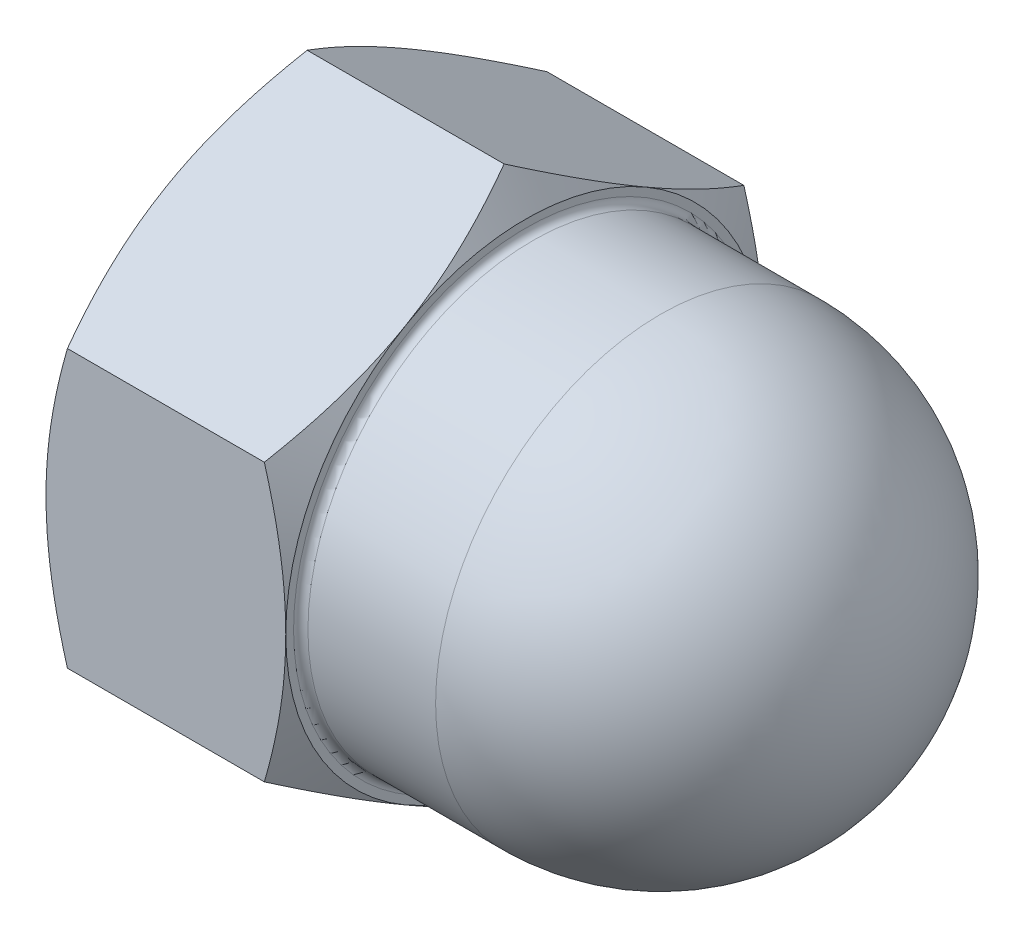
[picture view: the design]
ISO-10303-21;
HEADER;
FILE_DESCRIPTION(('STEP AP214'),'2;1');
FILE_NAME('part.step','',(''),(''),'','','');
FILE_SCHEMA(('AUTOMOTIVE_DESIGN { 1 0 10303 214 1 1 1 1 }'));
ENDSEC;
DATA;
#1=APPLICATION_CONTEXT('core data for automotive mechanical design processes');
#2=APPLICATION_PROTOCOL_DEFINITION('international standard','automotive_design',2000,#1);
#3=PRODUCT_CONTEXT('',#1,'mechanical');
#4=PRODUCT('Part','Part','',(#3));
#5=PRODUCT_RELATED_PRODUCT_CATEGORY('part','',(#4));
#6=PRODUCT_DEFINITION_FORMATION('','',#4);
#7=PRODUCT_DEFINITION_CONTEXT('part definition',#1,'design');
#8=PRODUCT_DEFINITION('design','',#6,#7);
#9=PRODUCT_DEFINITION_SHAPE('','',#8);
#10=(LENGTH_UNIT() NAMED_UNIT(*) SI_UNIT(.MILLI.,.METRE.));
#11=(NAMED_UNIT(*) PLANE_ANGLE_UNIT() SI_UNIT($,.RADIAN.));
#12=(NAMED_UNIT(*) SI_UNIT($,.STERADIAN.) SOLID_ANGLE_UNIT());
#13=UNCERTAINTY_MEASURE_WITH_UNIT(LENGTH_MEASURE(1.E-05),#10,'distance_accuracy_value','');
#14=(GEOMETRIC_REPRESENTATION_CONTEXT(3) GLOBAL_UNCERTAINTY_ASSIGNED_CONTEXT((#13)) GLOBAL_UNIT_ASSIGNED_CONTEXT((#10,
#11,#12)) REPRESENTATION_CONTEXT('',''));
#15=CARTESIAN_POINT('',(0.,0.,0.));
#16=DIRECTION('',(0.,0.,1.));
#17=DIRECTION('',(1.,0.,0.));
#18=AXIS2_PLACEMENT_3D('',#15,#16,#17);
#19=CARTESIAN_POINT('',(0.,4.61880215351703,0.));
#20=DIRECTION('',(-1.,0.,0.));
#21=DIRECTION('',(0.,0.,1.));
#22=AXIS2_PLACEMENT_3D('',#19,#20,#21);
#23=PLANE('',#22);
#24=CARTESIAN_POINT('',(0.,0.,0.));
#25=DIRECTION('',(-1.,0.,0.));
#26=DIRECTION('',(0.,0.,1.));
#27=AXIS2_PLACEMENT_3D('',#24,#25,#26);
#28=CIRCLE('',#27,2.5);
#29=CARTESIAN_POINT('',(0.,0.,2.5));
#30=VERTEX_POINT('',#29);
#31=EDGE_CURVE('E301',#30,#30,#28,.T.);
#32=ORIENTED_EDGE('',*,*,#31,.F.);
#33=EDGE_LOOP('',(#32));
#34=FACE_BOUND('',#33,.T.);
#35=CARTESIAN_POINT('',(0.,0.,0.));
#36=DIRECTION('',(-1.,0.,0.));
#37=DIRECTION('',(0.,0.,1.));
#38=AXIS2_PLACEMENT_3D('',#35,#36,#37);
#39=CIRCLE('',#38,4.);
#40=CARTESIAN_POINT('',(0.,-3.46410161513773,2.00000000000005));
#41=VERTEX_POINT('',#40);
#42=CARTESIAN_POINT('',(0.,0.,4.));
#43=VERTEX_POINT('',#42);
#44=EDGE_CURVE('E183',#41,#43,#39,.T.);
#45=ORIENTED_EDGE('',*,*,#44,.T.);
#46=CARTESIAN_POINT('',(0.,0.,0.));
#47=DIRECTION('',(-1.,0.,0.));
#48=DIRECTION('',(0.,0.,1.));
#49=AXIS2_PLACEMENT_3D('',#46,#47,#48);
#50=CIRCLE('',#49,4.);
#51=CARTESIAN_POINT('',(0.,3.46410161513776,1.99999999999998));
#52=VERTEX_POINT('',#51);
#53=EDGE_CURVE('E293',#43,#52,#50,.T.);
#54=ORIENTED_EDGE('',*,*,#53,.T.);
#55=CARTESIAN_POINT('',(0.,3.46410161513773,-2.00000000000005));
#56=VERTEX_POINT('',#55);
#57=EDGE_CURVE('E182',#52,#56,#39,.T.);
#58=ORIENTED_EDGE('',*,*,#57,.T.);
#59=CARTESIAN_POINT('',(0.,0.,-4.));
#60=VERTEX_POINT('',#59);
#61=EDGE_CURVE('E349',#56,#60,#39,.T.);
#62=ORIENTED_EDGE('',*,*,#61,.T.);
#63=CARTESIAN_POINT('',(0.,-3.46410161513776,-1.99999999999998));
#64=VERTEX_POINT('',#63);
#65=EDGE_CURVE('E348',#60,#64,#39,.T.);
#66=ORIENTED_EDGE('',*,*,#65,.T.);
#67=EDGE_CURVE('E346',#64,#41,#39,.T.);
#68=ORIENTED_EDGE('',*,*,#67,.T.);
#69=EDGE_LOOP('',(#45,#54,#58,#62,#66,#68));
#70=FACE_BOUND('',#69,.T.);
#71=ADVANCED_FACE('F32',(#34,#70),#23,.T.);
#72=CARTESIAN_POINT('',(4.,4.61880215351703,0.));
#73=DIRECTION('',(-1.,0.,0.));
#74=DIRECTION('',(0.,0.,1.));
#75=AXIS2_PLACEMENT_3D('',#72,#73,#74);
#76=PLANE('',#75);
#77=CARTESIAN_POINT('',(4.,0.,0.));
#78=DIRECTION('',(-1.,0.,0.));
#79=DIRECTION('',(0.,0.,1.));
#80=AXIS2_PLACEMENT_3D('',#77,#78,#79);
#81=CIRCLE('',#80,3.87);
#82=CARTESIAN_POINT('',(4.,0.,3.87));
#83=VERTEX_POINT('',#82);
#84=EDGE_CURVE('E11',#83,#83,#81,.T.);
#85=ORIENTED_EDGE('',*,*,#84,.T.);
#86=EDGE_LOOP('',(#85));
#87=FACE_BOUND('',#86,.T.);
#88=CARTESIAN_POINT('',(4.,0.,0.));
#89=DIRECTION('',(-1.,0.,0.));
#90=DIRECTION('',(0.,0.,1.));
#91=AXIS2_PLACEMENT_3D('',#88,#89,#90);
#92=CIRCLE('',#91,4.);
#93=CARTESIAN_POINT('',(4.,0.,4.));
#94=VERTEX_POINT('',#93);
#95=CARTESIAN_POINT('',(4.,3.46410161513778,1.99999999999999));
#96=VERTEX_POINT('',#95);
#97=EDGE_CURVE('E294',#94,#96,#92,.T.);
#98=ORIENTED_EDGE('',*,*,#97,.F.);
#99=CARTESIAN_POINT('',(4.,-3.46410161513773,2.00000000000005));
#100=VERTEX_POINT('',#99);
#101=EDGE_CURVE('E47',#100,#94,#92,.T.);
#102=ORIENTED_EDGE('',*,*,#101,.F.);
#103=CARTESIAN_POINT('',(4.,-3.46410161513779,-2.));
#104=VERTEX_POINT('',#103);
#105=EDGE_CURVE('E283',#104,#100,#92,.T.);
#106=ORIENTED_EDGE('',*,*,#105,.F.);
#107=CARTESIAN_POINT('',(4.,0.,-4.));
#108=VERTEX_POINT('',#107);
#109=EDGE_CURVE('E55',#108,#104,#92,.T.);
#110=ORIENTED_EDGE('',*,*,#109,.F.);
#111=CARTESIAN_POINT('',(4.,3.46410161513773,-2.00000000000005));
#112=VERTEX_POINT('',#111);
#113=EDGE_CURVE('E292',#112,#108,#92,.T.);
#114=ORIENTED_EDGE('',*,*,#113,.F.);
#115=EDGE_CURVE('E296',#96,#112,#92,.T.);
#116=ORIENTED_EDGE('',*,*,#115,.F.);
#117=EDGE_LOOP('',(#98,#102,#106,#110,#114,#116));
#118=FACE_BOUND('',#117,.T.);
#119=ADVANCED_FACE('F142',(#87,#118),#76,.F.);
#120=CARTESIAN_POINT('',(0.,0.,0.));
#121=DIRECTION('',(-1.,0.,0.));
#122=DIRECTION('',(0.,0.,1.));
#123=AXIS2_PLACEMENT_3D('',#120,#121,#122);
#124=CYLINDRICAL_SURFACE('',#123,3.75);
#125=CARTESIAN_POINT('',(4.12,0.,0.));
#126=DIRECTION('',(-1.,0.,0.));
#127=DIRECTION('',(0.,0.,1.));
#128=AXIS2_PLACEMENT_3D('',#125,#126,#127);
#129=CIRCLE('',#128,3.75);
#130=CARTESIAN_POINT('',(4.12,0.,3.75));
#131=VERTEX_POINT('',#130);
#132=EDGE_CURVE('E40',#131,#131,#129,.F.);
#133=ORIENTED_EDGE('',*,*,#132,.T.);
#134=EDGE_LOOP('',(#133));
#135=FACE_BOUND('',#134,.T.);
#136=CARTESIAN_POINT('',(6.25,0.,0.));
#137=DIRECTION('',(-1.,0.,0.));
#138=DIRECTION('',(0.,0.,1.));
#139=AXIS2_PLACEMENT_3D('',#136,#137,#138);
#140=CIRCLE('',#139,3.75);
#141=CARTESIAN_POINT('',(6.25,0.,3.75));
#142=VERTEX_POINT('',#141);
#143=EDGE_CURVE('E331',#142,#142,#140,.T.);
#144=ORIENTED_EDGE('',*,*,#143,.T.);
#145=EDGE_LOOP('',(#144));
#146=FACE_BOUND('',#145,.T.);
#147=ADVANCED_FACE('F148',(#135,#146),#124,.T.);
#148=CARTESIAN_POINT('',(6.25,0.,0.));
#149=DIRECTION('',(-1.,0.,0.));
#150=DIRECTION('',(0.,1.,0.));
#151=AXIS2_PLACEMENT_3D('',#148,#149,#150);
#152=SPHERICAL_SURFACE('',#151,3.75);
#153=ORIENTED_EDGE('',*,*,#143,.F.);
#154=EDGE_LOOP('',(#153));
#155=FACE_BOUND('',#154,.T.);
#156=ADVANCED_FACE('F465',(#155),#152,.T.);
#157=CARTESIAN_POINT('',(3.25783423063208,0.,0.));
#158=DIRECTION('',(-1.,0.,0.));
#159=DIRECTION('',(0.,0.,1.));
#160=AXIS2_PLACEMENT_3D('',#157,#158,#159);
#161=CONICAL_SURFACE('',#160,5.2854688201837,1.0471975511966);
#162=CARTESIAN_POINT('',(3.64266774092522,4.61891762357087,-0.000200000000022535));
#163=CARTESIAN_POINT('',(3.70128212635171,4.51743148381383,0.175579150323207));
#164=CARTESIAN_POINT('',(3.75458967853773,4.41506932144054,0.352875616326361));
#165=CARTESIAN_POINT('',(3.84763832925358,4.20857250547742,0.710538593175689));
#166=CARTESIAN_POINT('',(3.88734651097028,4.1044341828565,0.890911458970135));
#167=CARTESIAN_POINT('',(3.94915778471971,3.89744813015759,1.24942181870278));
#168=CARTESIAN_POINT('',(3.9716722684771,3.79463224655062,1.42750415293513));
#169=CARTESIAN_POINT('',(3.99854937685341,3.58851671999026,1.7845067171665));
#170=CARTESIAN_POINT('',(4.00293425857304,3.4852178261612,1.96342564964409));
#171=CARTESIAN_POINT('',(3.99380992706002,3.29219970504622,2.29774284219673));
#172=CARTESIAN_POINT('',(3.98254104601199,3.2024515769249,2.45319115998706));
#173=CARTESIAN_POINT('',(3.9468260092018,3.023540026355,2.76307505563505));
#174=CARTESIAN_POINT('',(3.92236765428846,2.93437722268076,2.91750956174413));
#175=CARTESIAN_POINT('',(3.8612239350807,2.75509682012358,3.22803232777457));
#176=CARTESIAN_POINT('',(3.82427939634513,2.66500191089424,3.3840812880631));
#177=CARTESIAN_POINT('',(3.74042992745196,2.48615580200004,3.69385183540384));
#178=CARTESIAN_POINT('',(3.69354469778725,2.39740231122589,3.84757739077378));
#179=CARTESIAN_POINT('',(3.64266774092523,2.30928560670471,4.0002));
#180=B_SPLINE_CURVE_WITH_KNOTS('',3,(#162,#163,#164,#165,#166,#167,#168,#169,#170,#171,#172,
#173,#174,#175,#176,#177,#178,#179),.UNSPECIFIED.,.F.,.F.,(4,2,2,2,2,2,2,2,4),(0.,
0.634047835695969,1.26961969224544,1.88946157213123,2.50854226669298,3.04757825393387,
3.58711366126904,4.13861653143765,4.68903648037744),.UNSPECIFIED.);
#181=CARTESIAN_POINT('',(3.64273441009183,4.61880215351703,0.));
#182=VERTEX_POINT('',#181);
#183=EDGE_CURVE('E209',#182,#96,#180,.T.);
#184=ORIENTED_EDGE('',*,*,#183,.T.);
#185=ORIENTED_EDGE('',*,*,#115,.T.);
#186=CARTESIAN_POINT('',(3.64266774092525,2.30928560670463,-4.0002));
#187=CARTESIAN_POINT('',(3.70128212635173,2.41077174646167,-3.82442084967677));
#188=CARTESIAN_POINT('',(3.75458967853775,2.51313390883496,-3.64712438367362));
#189=CARTESIAN_POINT('',(3.84763832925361,2.71963072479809,-3.2894614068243));
#190=CARTESIAN_POINT('',(3.8873465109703,2.82376904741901,-3.10908854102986));
#191=CARTESIAN_POINT('',(3.94915778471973,3.03075510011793,-2.75057818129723));
#192=CARTESIAN_POINT('',(3.97167226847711,3.1335709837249,-2.57249584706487));
#193=CARTESIAN_POINT('',(3.99854937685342,3.33968651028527,-2.21549328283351));
#194=CARTESIAN_POINT('',(4.00293425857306,3.44298540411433,-2.03657435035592));
#195=CARTESIAN_POINT('',(3.99380992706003,3.63600352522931,-1.70225715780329));
#196=CARTESIAN_POINT('',(3.982541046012,3.72575165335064,-1.54680884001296));
#197=CARTESIAN_POINT('',(3.9468260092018,3.90466320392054,-1.23692494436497));
#198=CARTESIAN_POINT('',(3.92236765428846,3.99382600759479,-1.08249043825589));
#199=CARTESIAN_POINT('',(3.8612239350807,4.17310641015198,-0.771967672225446));
#200=CARTESIAN_POINT('',(3.82427939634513,4.26320131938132,-0.615918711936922));
#201=CARTESIAN_POINT('',(3.74042992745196,4.44204742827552,-0.306148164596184));
#202=CARTESIAN_POINT('',(3.69354469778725,4.53080091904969,-0.152422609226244));
#203=CARTESIAN_POINT('',(3.64266774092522,4.61891762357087,0.00019999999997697));
#204=B_SPLINE_CURVE_WITH_KNOTS('',3,(#186,#187,#188,#189,#190,#191,#192,#193,#194,#195,#196,
#197,#198,#199,#200,#201,#202,#203),.UNSPECIFIED.,.F.,.F.,(4,2,2,2,2,2,2,2,4),(0.,
0.634047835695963,1.26961969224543,1.88946157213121,2.50854226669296,3.04757825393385,
3.58711366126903,4.13861653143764,4.68903648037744),.UNSPECIFIED.);
#205=EDGE_CURVE('E174',#112,#182,#204,.T.);
#206=ORIENTED_EDGE('',*,*,#205,.T.);
#207=EDGE_LOOP('',(#184,#185,#206));
#208=FACE_BOUND('',#207,.T.);
#209=ADVANCED_FACE('F192',(#208),#161,.T.);
#210=CARTESIAN_POINT('',(3.64273441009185,2.30940107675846,-4.));
#211=VERTEX_POINT('',#210);
#212=EDGE_CURVE('E181',#211,#112,#204,.T.);
#213=ORIENTED_EDGE('',*,*,#212,.T.);
#214=ORIENTED_EDGE('',*,*,#113,.T.);
#215=CARTESIAN_POINT('',(2.05997480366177,-6.17841977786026,-4.));
#216=CARTESIAN_POINT('',(2.14452061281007,-6.00392359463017,-4.));
#217=CARTESIAN_POINT('',(2.22824852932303,-5.829024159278,-4.));
#218=CARTESIAN_POINT('',(2.39360807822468,-5.47820424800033,-4.));
#219=CARTESIAN_POINT('',(2.47523937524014,-5.30228361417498,-4.));
#220=CARTESIAN_POINT('',(2.63636123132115,-4.94828833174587,-4.));
#221=CARTESIAN_POINT('',(2.7158374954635,-4.77020715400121,-4.));
#222=CARTESIAN_POINT('',(2.8715041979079,-4.41261967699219,-4.));
#223=CARTESIAN_POINT('',(2.94769479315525,-4.23311344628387,-4.));
#224=CARTESIAN_POINT('',(3.09826529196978,-3.86668749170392,-4.));
#225=CARTESIAN_POINT('',(3.17251195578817,-3.67971271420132,-4.));
#226=CARTESIAN_POINT('',(3.31532541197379,-3.30356643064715,-4.));
#227=CARTESIAN_POINT('',(3.38389156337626,-3.11439467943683,-4.));
#228=CARTESIAN_POINT('',(3.51352569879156,-2.73391578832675,-4.));
#229=CARTESIAN_POINT('',(3.57460908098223,-2.5426139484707,-4.));
#230=CARTESIAN_POINT('',(3.68730110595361,-2.15726633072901,-4.));
#231=CARTESIAN_POINT('',(3.73891275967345,-1.96322144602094,-4.));
#232=CARTESIAN_POINT('',(3.82989407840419,-1.57335309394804,-4.));
#233=CARTESIAN_POINT('',(3.86932936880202,-1.37754523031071,-4.));
#234=CARTESIAN_POINT('',(3.93371281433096,-0.983520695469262,-4.));
#235=CARTESIAN_POINT('',(3.95866229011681,-0.785304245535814,-4.));
#236=CARTESIAN_POINT('',(3.99175666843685,-0.39003087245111,-4.));
#237=CARTESIAN_POINT('',(4.00011559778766,-0.192992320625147,-4.));
#238=CARTESIAN_POINT('',(3.99988203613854,0.201089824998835,-4.));
#239=CARTESIAN_POINT('',(3.99128917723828,0.398133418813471,-4.));
#240=CARTESIAN_POINT('',(3.96285041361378,0.733403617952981,-4.));
#241=CARTESIAN_POINT('',(3.94702668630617,0.87199151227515,-4.));
#242=CARTESIAN_POINT('',(3.90799223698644,1.14813026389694,-4.));
#243=CARTESIAN_POINT('',(3.88478048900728,1.28568097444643,-4.));
#244=CARTESIAN_POINT('',(3.80528561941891,1.69660728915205,-4.));
#245=CARTESIAN_POINT('',(3.73915808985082,1.96809847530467,-4.));
#246=CARTESIAN_POINT('',(3.6247811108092,2.37400802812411,-4.));
#247=CARTESIAN_POINT('',(3.58360096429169,2.51053794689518,-4.));
#248=CARTESIAN_POINT('',(3.49703582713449,2.78227101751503,-4.));
#249=CARTESIAN_POINT('',(3.45165080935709,2.91747416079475,-4.));
#250=CARTESIAN_POINT('',(3.35739819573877,3.18659783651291,-4.));
#251=CARTESIAN_POINT('',(3.30853179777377,3.32051879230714,-4.));
#252=CARTESIAN_POINT('',(3.20788408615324,3.5872561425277,-4.));
#253=CARTESIAN_POINT('',(3.15610280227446,3.72007254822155,-4.));
#254=CARTESIAN_POINT('',(3.03339460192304,4.02646162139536,-4.));
#255=CARTESIAN_POINT('',(2.9615797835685,4.19967796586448,-4.));
#256=CARTESIAN_POINT('',(2.81461065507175,4.54469195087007,-4.));
#257=CARTESIAN_POINT('',(2.73945616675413,4.71648951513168,-4.));
#258=CARTESIAN_POINT('',(2.58645916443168,5.05891813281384,-4.));
#259=CARTESIAN_POINT('',(2.50861616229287,5.22954896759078,-4.));
#260=CARTESIAN_POINT('',(2.35076039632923,5.56980548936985,-4.));
#261=CARTESIAN_POINT('',(2.27074758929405,5.73943115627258,-4.));
#262=CARTESIAN_POINT('',(2.02792164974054,6.24735568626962,-4.));
#263=CARTESIAN_POINT('',(1.86246273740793,6.58438902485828,-4.));
#264=CARTESIAN_POINT('',(1.5267209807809,7.25604338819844,-4.));
#265=CARTESIAN_POINT('',(1.35643796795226,7.59066432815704,-4.));
#266=CARTESIAN_POINT('',(1.02626627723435,8.23125888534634,-4.));
#267=CARTESIAN_POINT('',(0.866644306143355,8.53737022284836,-4.));
#268=CARTESIAN_POINT('',(0.545195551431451,9.14844363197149,-4.));
#269=CARTESIAN_POINT('',(0.383368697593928,9.45340566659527,-4.));
#270=CARTESIAN_POINT('',(0.0584065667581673,10.0617154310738,-4.));
#271=CARTESIAN_POINT('',(-0.104724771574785,10.3650652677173,-4.));
#272=CARTESIAN_POINT('',(-0.432318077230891,10.9710255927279,-4.));
#273=CARTESIAN_POINT('',(-0.596779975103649,11.2736361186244,-4.));
#274=CARTESIAN_POINT('',(-0.761740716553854,11.5759724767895,-4.));
#275=B_SPLINE_CURVE_WITH_KNOTS('',3,(#215,#216,#217,#218,#219,#220,#221,#222,#223,#224,#225,
#226,#227,#228,#229,#230,#231,#232,#233,#234,#235,#236,#237,#238,#239,#240,#241,#242,#243,#244,
#245,#246,#247,#248,#249,#250,#251,#252,#253,#254,#255,#256,#257,#258,#259,#260,#261,#262,#263,
#264,#265,#266,#267,#268,#269,#270,#271,#272,#273,#274),.UNSPECIFIED.,.F.,.F.,(4,2,2,2,2,2,2,2,
2,2,2,2,2,2,2,2,2,2,2,2,2,2,2,2,2,2,2,2,2,4),(0.,0.581704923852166,1.16350232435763,
1.74850946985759,2.33348864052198,2.93694794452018,3.54047524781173,4.14273896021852,
4.74481088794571,5.3435788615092,5.9422922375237,6.53323035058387,7.12418128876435,
7.54244285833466,7.96076253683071,8.79787772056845,9.22565783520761,9.65344071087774,
10.0810770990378,10.5087091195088,11.0712028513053,11.6337266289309,12.1963530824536,
12.7589907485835,13.8852967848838,15.011642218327,16.0473185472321,17.0830279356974,
18.1163183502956,19.1495551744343),.UNSPECIFIED.);
#276=EDGE_CURVE('E202',#211,#108,#275,.F.);
#277=ORIENTED_EDGE('',*,*,#276,.F.);
#278=EDGE_LOOP('',(#213,#214,#277));
#279=FACE_BOUND('',#278,.T.);
#280=ADVANCED_FACE('F187',(#279),#161,.T.);
#281=CARTESIAN_POINT('',(3.64266774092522,-4.61891762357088,0.000200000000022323));
#282=CARTESIAN_POINT('',(3.7012821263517,-4.51743148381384,-0.175579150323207));
#283=CARTESIAN_POINT('',(3.75458967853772,-4.41506932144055,-0.352875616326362));
#284=CARTESIAN_POINT('',(3.84763832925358,-4.20857250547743,-0.710538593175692));
#285=CARTESIAN_POINT('',(3.88734651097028,-4.1044341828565,-0.890911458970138));
#286=CARTESIAN_POINT('',(3.9491577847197,-3.8974481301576,-1.24942181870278));
#287=CARTESIAN_POINT('',(3.97167226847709,-3.79463224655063,-1.42750415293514));
#288=CARTESIAN_POINT('',(3.9985493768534,-3.58851671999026,-1.78450671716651));
#289=CARTESIAN_POINT('',(4.00293425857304,-3.48521782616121,-1.9634256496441));
#290=CARTESIAN_POINT('',(3.99380992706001,-3.29219970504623,-2.29774284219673));
#291=CARTESIAN_POINT('',(3.98254104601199,-3.2024515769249,-2.45319115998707));
#292=CARTESIAN_POINT('',(3.94682600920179,-3.02354002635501,-2.76307505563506));
#293=CARTESIAN_POINT('',(3.92236765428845,-2.93437722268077,-2.91750956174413));
#294=CARTESIAN_POINT('',(3.86122393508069,-2.75509682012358,-3.22803232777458));
#295=CARTESIAN_POINT('',(3.82427939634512,-2.66500191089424,-3.3840812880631));
#296=CARTESIAN_POINT('',(3.74042992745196,-2.48615580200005,-3.69385183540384));
#297=CARTESIAN_POINT('',(3.69354469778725,-2.3974023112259,-3.84757739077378));
#298=CARTESIAN_POINT('',(3.64266774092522,-2.30928560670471,-4.0002));
#299=B_SPLINE_CURVE_WITH_KNOTS('',3,(#281,#282,#283,#284,#285,#286,#287,#288,#289,#290,#291,
#292,#293,#294,#295,#296,#297,#298),.UNSPECIFIED.,.F.,.F.,(4,2,2,2,2,2,2,2,4),(0.,
0.634047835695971,1.26961969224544,1.88946157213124,2.50854226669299,3.04757825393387,
3.58711366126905,4.13861653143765,4.68903648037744),.UNSPECIFIED.);
#300=CARTESIAN_POINT('',(3.64273441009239,-2.3094010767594,-4.));
#301=VERTEX_POINT('',#300);
#302=EDGE_CURVE('E214',#104,#301,#299,.T.);
#303=ORIENTED_EDGE('',*,*,#302,.T.);
#304=EDGE_CURVE('E269',#108,#301,#275,.F.);
#305=ORIENTED_EDGE('',*,*,#304,.F.);
#306=ORIENTED_EDGE('',*,*,#109,.T.);
#307=EDGE_LOOP('',(#303,#305,#306));
#308=FACE_BOUND('',#307,.T.);
#309=ADVANCED_FACE('F191',(#308),#161,.T.);
#310=CARTESIAN_POINT('',(3.64266774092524,-2.30928560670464,4.0002));
#311=CARTESIAN_POINT('',(3.70128212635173,-2.41077174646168,3.82442084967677));
#312=CARTESIAN_POINT('',(3.75458967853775,-2.51313390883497,3.64712438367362));
#313=CARTESIAN_POINT('',(3.8476383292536,-2.7196307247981,3.2894614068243));
#314=CARTESIAN_POINT('',(3.8873465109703,-2.82376904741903,3.10908854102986));
#315=CARTESIAN_POINT('',(3.94915778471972,-3.03075510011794,2.75057818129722));
#316=CARTESIAN_POINT('',(3.97167226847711,-3.13357098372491,2.57249584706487));
#317=CARTESIAN_POINT('',(3.99854937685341,-3.33968651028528,2.21549328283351));
#318=CARTESIAN_POINT('',(4.00293425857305,-3.44298540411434,2.03657435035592));
#319=CARTESIAN_POINT('',(3.99380992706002,-3.63600352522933,1.70225715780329));
#320=CARTESIAN_POINT('',(3.982541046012,-3.72575165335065,1.54680884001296));
#321=CARTESIAN_POINT('',(3.9468260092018,-3.90466320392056,1.23692494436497));
#322=CARTESIAN_POINT('',(3.92236765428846,-3.9938260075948,1.08249043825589));
#323=CARTESIAN_POINT('',(3.8612239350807,-4.17310641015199,0.771967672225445));
#324=CARTESIAN_POINT('',(3.82427939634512,-4.26320131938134,0.61591871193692));
#325=CARTESIAN_POINT('',(3.74042992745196,-4.44204742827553,0.306148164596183));
#326=CARTESIAN_POINT('',(3.69354469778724,-4.5308009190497,0.152422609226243));
#327=CARTESIAN_POINT('',(3.64266774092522,-4.61891762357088,-0.000199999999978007));
#328=B_SPLINE_CURVE_WITH_KNOTS('',3,(#310,#311,#312,#313,#314,#315,#316,#317,#318,#319,#320,
#321,#322,#323,#324,#325,#326,#327),.UNSPECIFIED.,.F.,.F.,(4,2,2,2,2,2,2,2,4),(0.,
0.634047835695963,1.26961969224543,1.88946157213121,2.50854226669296,3.04757825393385,
3.58711366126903,4.13861653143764,4.68903648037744),.UNSPECIFIED.);
#329=CARTESIAN_POINT('',(3.64273441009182,-4.61880215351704,0.));
#330=VERTEX_POINT('',#329);
#331=EDGE_CURVE('E219',#100,#330,#328,.T.);
#332=ORIENTED_EDGE('',*,*,#331,.T.);
#333=EDGE_CURVE('E225',#330,#104,#299,.T.);
#334=ORIENTED_EDGE('',*,*,#333,.T.);
#335=ORIENTED_EDGE('',*,*,#105,.T.);
#336=EDGE_LOOP('',(#332,#334,#335));
#337=FACE_BOUND('',#336,.T.);
#338=ADVANCED_FACE('F281',(#337),#161,.T.);
#339=CARTESIAN_POINT('',(2.05997480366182,-6.17841977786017,4.));
#340=CARTESIAN_POINT('',(2.14452061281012,-6.00392359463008,4.));
#341=CARTESIAN_POINT('',(2.22824852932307,-5.8290241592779,4.));
#342=CARTESIAN_POINT('',(2.39360807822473,-5.47820424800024,4.));
#343=CARTESIAN_POINT('',(2.47523937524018,-5.30228361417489,4.));
#344=CARTESIAN_POINT('',(2.63636123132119,-4.94828833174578,4.));
#345=CARTESIAN_POINT('',(2.71583749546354,-4.77020715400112,4.));
#346=CARTESIAN_POINT('',(2.87150419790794,-4.4126196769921,4.));
#347=CARTESIAN_POINT('',(2.94769479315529,-4.23311344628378,4.));
#348=CARTESIAN_POINT('',(3.09826529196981,-3.86668749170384,4.));
#349=CARTESIAN_POINT('',(3.1725119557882,-3.67971271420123,4.));
#350=CARTESIAN_POINT('',(3.31532541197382,-3.30356643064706,4.));
#351=CARTESIAN_POINT('',(3.38389156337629,-3.11439467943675,4.));
#352=CARTESIAN_POINT('',(3.51352569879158,-2.73391578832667,4.));
#353=CARTESIAN_POINT('',(3.57460908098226,-2.54261394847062,4.));
#354=CARTESIAN_POINT('',(3.68730110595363,-2.15726633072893,4.));
#355=CARTESIAN_POINT('',(3.73891275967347,-1.96322144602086,4.));
#356=CARTESIAN_POINT('',(3.82989407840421,-1.57335309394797,4.));
#357=CARTESIAN_POINT('',(3.86932936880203,-1.37754523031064,4.));
#358=CARTESIAN_POINT('',(3.93371281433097,-0.98352069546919,4.));
#359=CARTESIAN_POINT('',(3.95866229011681,-0.785304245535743,4.));
#360=CARTESIAN_POINT('',(3.99175666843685,-0.390030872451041,4.));
#361=CARTESIAN_POINT('',(4.00011559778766,-0.192992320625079,4.));
#362=CARTESIAN_POINT('',(3.99988203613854,0.2010898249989,4.));
#363=CARTESIAN_POINT('',(3.99128917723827,0.398133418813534,4.));
#364=CARTESIAN_POINT('',(3.96285041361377,0.733403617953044,4.));
#365=CARTESIAN_POINT('',(3.94702668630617,0.871991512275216,4.));
#366=CARTESIAN_POINT('',(3.90799223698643,1.14813026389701,4.));
#367=CARTESIAN_POINT('',(3.88478048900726,1.28568097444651,4.));
#368=CARTESIAN_POINT('',(3.80528561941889,1.69660728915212,4.));
#369=CARTESIAN_POINT('',(3.7391580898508,1.96809847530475,4.));
#370=CARTESIAN_POINT('',(3.62478111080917,2.37400802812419,4.));
#371=CARTESIAN_POINT('',(3.58360096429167,2.51053794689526,4.));
#372=CARTESIAN_POINT('',(3.49703582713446,2.78227101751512,4.));
#373=CARTESIAN_POINT('',(3.45165080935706,2.91747416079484,4.));
#374=CARTESIAN_POINT('',(3.35739819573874,3.186597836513,4.));
#375=CARTESIAN_POINT('',(3.30853179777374,3.32051879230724,4.));
#376=CARTESIAN_POINT('',(3.2078840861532,3.5872561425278,4.));
#377=CARTESIAN_POINT('',(3.15610280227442,3.72007254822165,4.));
#378=CARTESIAN_POINT('',(3.033394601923,4.02646162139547,4.));
#379=CARTESIAN_POINT('',(2.96157978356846,4.19967796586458,4.));
#380=CARTESIAN_POINT('',(2.8146106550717,4.54469195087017,4.));
#381=CARTESIAN_POINT('',(2.73945616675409,4.71648951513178,4.));
#382=CARTESIAN_POINT('',(2.58645916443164,5.05891813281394,4.));
#383=CARTESIAN_POINT('',(2.50861616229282,5.22954896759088,4.));
#384=CARTESIAN_POINT('',(2.35076039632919,5.56980548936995,4.));
#385=CARTESIAN_POINT('',(2.27074758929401,5.73943115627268,4.));
#386=CARTESIAN_POINT('',(2.02792164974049,6.24735568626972,4.));
#387=CARTESIAN_POINT('',(1.86246273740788,6.58438902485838,4.));
#388=CARTESIAN_POINT('',(1.52672098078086,7.25604338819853,4.));
#389=CARTESIAN_POINT('',(1.35643796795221,7.59066432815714,4.));
#390=CARTESIAN_POINT('',(1.0262662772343,8.23125888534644,4.));
#391=CARTESIAN_POINT('',(0.866644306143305,8.53737022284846,4.));
#392=CARTESIAN_POINT('',(0.545195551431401,9.14844363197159,4.));
#393=CARTESIAN_POINT('',(0.383368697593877,9.45340566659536,4.));
#394=CARTESIAN_POINT('',(0.0584065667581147,10.0617154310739,4.));
#395=CARTESIAN_POINT('',(-0.104724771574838,10.3650652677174,4.));
#396=CARTESIAN_POINT('',(-0.432318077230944,10.9710255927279,4.));
#397=CARTESIAN_POINT('',(-0.596779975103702,11.2736361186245,4.));
#398=CARTESIAN_POINT('',(-0.761740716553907,11.5759724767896,4.));
#399=B_SPLINE_CURVE_WITH_KNOTS('',3,(#339,#340,#341,#342,#343,#344,#345,#346,#347,#348,#349,
#350,#351,#352,#353,#354,#355,#356,#357,#358,#359,#360,#361,#362,#363,#364,#365,#366,#367,#368,
#369,#370,#371,#372,#373,#374,#375,#376,#377,#378,#379,#380,#381,#382,#383,#384,#385,#386,#387,
#388,#389,#390,#391,#392,#393,#394,#395,#396,#397,#398),.UNSPECIFIED.,.F.,.F.,(4,2,2,2,2,2,2,2,
2,2,2,2,2,2,2,2,2,2,2,2,2,2,2,2,2,2,2,2,2,4),(0.,0.581704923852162,1.16350232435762,
1.74850946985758,2.33348864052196,2.93694794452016,3.54047524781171,4.1427389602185,
4.74481088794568,5.34357886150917,5.94229223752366,6.53323035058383,7.12418128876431,
7.54244285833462,7.96076253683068,8.79787772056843,9.2256578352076,9.65344071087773,
10.0810770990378,10.5087091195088,11.0712028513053,11.6337266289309,12.1963530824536,
12.7589907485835,13.8852967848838,15.011642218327,16.0473185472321,17.0830279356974,
18.1163183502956,19.1495551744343),.UNSPECIFIED.);
#400=CARTESIAN_POINT('',(3.64273441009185,-2.30940107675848,4.));
#401=VERTEX_POINT('',#400);
#402=EDGE_CURVE('E226',#94,#401,#399,.F.);
#403=ORIENTED_EDGE('',*,*,#402,.T.);
#404=EDGE_CURVE('E224',#401,#100,#328,.T.);
#405=ORIENTED_EDGE('',*,*,#404,.T.);
#406=ORIENTED_EDGE('',*,*,#101,.T.);
#407=EDGE_LOOP('',(#403,#405,#406));
#408=FACE_BOUND('',#407,.T.);
#409=ADVANCED_FACE('F501',(#408),#161,.T.);
#410=CARTESIAN_POINT('',(3.64273441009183,2.30940107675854,4.));
#411=VERTEX_POINT('',#410);
#412=EDGE_CURVE('E274',#96,#411,#180,.T.);
#413=ORIENTED_EDGE('',*,*,#412,.T.);
#414=EDGE_CURVE('E566',#411,#94,#399,.F.);
#415=ORIENTED_EDGE('',*,*,#414,.T.);
#416=ORIENTED_EDGE('',*,*,#97,.T.);
#417=EDGE_LOOP('',(#413,#415,#416));
#418=FACE_BOUND('',#417,.T.);
#419=ADVANCED_FACE('F160',(#418),#161,.T.);
#420=CARTESIAN_POINT('',(4.,2.30940107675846,-4.));
#421=DIRECTION('',(0.,-0.866025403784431,0.500000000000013));
#422=DIRECTION('',(0.,-0.500000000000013,-0.866025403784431));
#423=AXIS2_PLACEMENT_3D('',#420,#421,#422);
#424=PLANE('',#423);
#425=ORIENTED_EDGE('',*,*,#212,.F.);
#426=DIRECTION('',(-1.,0.,0.));
#427=VECTOR('',#426,1.);
#428=CARTESIAN_POINT('',(4.,2.30940107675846,-4.));
#429=LINE('',#428,#427);
#430=CARTESIAN_POINT('',(0.357265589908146,2.30940107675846,-4.));
#431=VERTEX_POINT('',#430);
#432=EDGE_CURVE('E330',#211,#431,#429,.T.);
#433=ORIENTED_EDGE('',*,*,#432,.T.);
#434=CARTESIAN_POINT('',(0.357332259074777,4.61891762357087,0.000199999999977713));
#435=CARTESIAN_POINT('',(0.298717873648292,4.51743148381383,-0.175579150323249));
#436=CARTESIAN_POINT('',(0.245410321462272,4.41506932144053,-0.352875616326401));
#437=CARTESIAN_POINT('',(0.152361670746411,4.20857250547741,-0.710538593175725));
#438=CARTESIAN_POINT('',(0.112653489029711,4.10443418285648,-0.890911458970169));
#439=CARTESIAN_POINT('',(0.050842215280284,3.89744813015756,-1.24942181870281));
#440=CARTESIAN_POINT('',(0.0283277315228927,3.7946322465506,-1.42750415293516));
#441=CARTESIAN_POINT('',(0.00145062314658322,3.58851671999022,-1.78450671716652));
#442=CARTESIAN_POINT('',(-0.00293425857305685,3.48521782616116,-1.96342564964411));
#443=CARTESIAN_POINT('',(0.00619007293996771,3.29219970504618,-2.29774284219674));
#444=CARTESIAN_POINT('',(0.0174589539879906,3.20245157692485,-2.45319115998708));
#445=CARTESIAN_POINT('',(0.0531739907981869,3.02354002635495,-2.76307505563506));
#446=CARTESIAN_POINT('',(0.0776323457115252,2.9343772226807,-2.91750956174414));
#447=CARTESIAN_POINT('',(0.138776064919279,2.75509682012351,-3.22803232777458));
#448=CARTESIAN_POINT('',(0.175720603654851,2.66500191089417,-3.38408128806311));
#449=CARTESIAN_POINT('',(0.259570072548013,2.48615580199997,-3.69385183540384));
#450=CARTESIAN_POINT('',(0.306455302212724,2.39740231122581,-3.84757739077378));
#451=CARTESIAN_POINT('',(0.35733225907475,2.30928560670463,-4.0002));
#452=B_SPLINE_CURVE_WITH_KNOTS('',3,(#434,#435,#436,#437,#438,#439,#440,#441,#442,#443,#444,
#445,#446,#447,#448,#449,#450,#451),.UNSPECIFIED.,.F.,.F.,(4,2,2,2,2,2,2,2,4),(0.,
0.634047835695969,1.26961969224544,1.88946157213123,2.50854226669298,3.04757825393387,
3.58711366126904,4.13861653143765,4.68903648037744),.UNSPECIFIED.);
#453=EDGE_CURVE('E166',#56,#431,#452,.T.);
#454=ORIENTED_EDGE('',*,*,#453,.F.);
#455=CARTESIAN_POINT('',(0.357265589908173,4.61880215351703,0.));
#456=VERTEX_POINT('',#455);
#457=EDGE_CURVE('E327',#456,#56,#452,.T.);
#458=ORIENTED_EDGE('',*,*,#457,.F.);
#459=DIRECTION('',(-1.,0.,0.));
#460=VECTOR('',#459,1.);
#461=CARTESIAN_POINT('',(4.,4.61880215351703,0.));
#462=LINE('',#461,#460);
#463=EDGE_CURVE('E324',#182,#456,#462,.T.);
#464=ORIENTED_EDGE('',*,*,#463,.F.);
#465=ORIENTED_EDGE('',*,*,#205,.F.);
#466=EDGE_LOOP('',(#425,#433,#454,#458,#464,#465));
#467=FACE_BOUND('',#466,.T.);
#468=ADVANCED_FACE('F155',(#467),#424,.F.);
#469=CARTESIAN_POINT('',(4.,2.30940107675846,-4.));
#470=DIRECTION('',(0.,0.,-1.));
#471=DIRECTION('',(-1.,0.,0.));
#472=AXIS2_PLACEMENT_3D('',#469,#470,#471);
#473=PLANE('',#472);
#474=ORIENTED_EDGE('',*,*,#432,.F.);
#475=ORIENTED_EDGE('',*,*,#276,.T.);
#476=ORIENTED_EDGE('',*,*,#304,.T.);
#477=DIRECTION('',(-1.,0.,0.));
#478=VECTOR('',#477,1.);
#479=CARTESIAN_POINT('',(4.,-2.30940107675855,-4.));
#480=LINE('',#479,#478);
#481=CARTESIAN_POINT('',(0.357265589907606,-2.3094010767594,-4.));
#482=VERTEX_POINT('',#481);
#483=EDGE_CURVE('E288',#301,#482,#480,.T.);
#484=ORIENTED_EDGE('',*,*,#483,.T.);
#485=CARTESIAN_POINT('',(1.94002519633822,-6.17841977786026,-4.));
#486=CARTESIAN_POINT('',(1.85547938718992,-6.00392359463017,-4.));
#487=CARTESIAN_POINT('',(1.77175147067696,-5.829024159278,-4.));
#488=CARTESIAN_POINT('',(1.60639192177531,-5.47820424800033,-4.));
#489=CARTESIAN_POINT('',(1.52476062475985,-5.30228361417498,-4.));
#490=CARTESIAN_POINT('',(1.36363876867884,-4.94828833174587,-4.));
#491=CARTESIAN_POINT('',(1.2841625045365,-4.77020715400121,-4.));
#492=CARTESIAN_POINT('',(1.12849580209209,-4.41261967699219,-4.));
#493=CARTESIAN_POINT('',(1.05230520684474,-4.23311344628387,-4.));
#494=CARTESIAN_POINT('',(0.901734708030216,-3.86668749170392,-4.));
#495=CARTESIAN_POINT('',(0.827488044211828,-3.67971271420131,-4.));
#496=CARTESIAN_POINT('',(0.684674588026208,-3.30356643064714,-4.));
#497=CARTESIAN_POINT('',(0.616108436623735,-3.11439467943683,-4.));
#498=CARTESIAN_POINT('',(0.48647430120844,-2.73391578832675,-4.));
#499=CARTESIAN_POINT('',(0.425390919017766,-2.5426139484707,-4.));
#500=CARTESIAN_POINT('',(0.312698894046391,-2.15726633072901,-4.));
#501=CARTESIAN_POINT('',(0.261087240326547,-1.96322144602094,-4.));
#502=CARTESIAN_POINT('',(0.170105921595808,-1.57335309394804,-4.));
#503=CARTESIAN_POINT('',(0.130670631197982,-1.37754523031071,-4.));
#504=CARTESIAN_POINT('',(0.0662871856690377,-0.983520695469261,-4.));
#505=CARTESIAN_POINT('',(0.0413377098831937,-0.785304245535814,-4.));
#506=CARTESIAN_POINT('',(0.00824333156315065,-0.390030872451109,-4.));
#507=CARTESIAN_POINT('',(-0.000115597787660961,-0.192992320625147,-4.));
#508=CARTESIAN_POINT('',(0.000117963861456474,0.201089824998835,-4.));
#509=CARTESIAN_POINT('',(0.00871082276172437,0.39813341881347,-4.));
#510=CARTESIAN_POINT('',(0.0371495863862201,0.733403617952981,-4.));
#511=CARTESIAN_POINT('',(0.0529733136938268,0.871991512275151,-4.));
#512=CARTESIAN_POINT('',(0.0920077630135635,1.14813026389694,-4.));
#513=CARTESIAN_POINT('',(0.115219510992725,1.28568097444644,-4.));
#514=CARTESIAN_POINT('',(0.194714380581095,1.69660728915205,-4.));
#515=CARTESIAN_POINT('',(0.260841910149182,1.96809847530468,-4.));
#516=CARTESIAN_POINT('',(0.375218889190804,2.37400802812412,-4.));
#517=CARTESIAN_POINT('',(0.416399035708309,2.51053794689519,-4.));
#518=CARTESIAN_POINT('',(0.502964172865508,2.78227101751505,-4.));
#519=CARTESIAN_POINT('',(0.548349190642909,2.91747416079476,-4.));
#520=CARTESIAN_POINT('',(0.642601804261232,3.18659783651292,-4.));
#521=CARTESIAN_POINT('',(0.69146820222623,3.32051879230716,-4.));
#522=CARTESIAN_POINT('',(0.792115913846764,3.58725614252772,-4.));
#523=CARTESIAN_POINT('',(0.843897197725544,3.72007254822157,-4.));
#524=CARTESIAN_POINT('',(0.966605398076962,4.02646162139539,-4.));
#525=CARTESIAN_POINT('',(1.0384202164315,4.1996779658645,-4.));
#526=CARTESIAN_POINT('',(1.18538934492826,4.54469195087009,-4.));
#527=CARTESIAN_POINT('',(1.26054383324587,4.7164895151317,-4.));
#528=CARTESIAN_POINT('',(1.41354083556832,5.05891813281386,-4.));
#529=CARTESIAN_POINT('',(1.49138383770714,5.2295489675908,-4.));
#530=CARTESIAN_POINT('',(1.64923960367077,5.56980548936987,-4.));
#531=CARTESIAN_POINT('',(1.72925241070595,5.7394311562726,-4.));
#532=CARTESIAN_POINT('',(1.97207835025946,6.24735568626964,-4.));
#533=CARTESIAN_POINT('',(2.13753726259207,6.58438902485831,-4.));
#534=CARTESIAN_POINT('',(2.47327901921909,7.25604338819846,-4.));
#535=CARTESIAN_POINT('',(2.64356203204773,7.59066432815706,-4.));
#536=CARTESIAN_POINT('',(2.97373372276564,8.23125888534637,-4.));
#537=CARTESIAN_POINT('',(3.13335569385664,8.53737022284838,-4.));
#538=CARTESIAN_POINT('',(3.45480444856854,9.14844363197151,-4.));
#539=CARTESIAN_POINT('',(3.61663130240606,9.45340566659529,-4.));
#540=CARTESIAN_POINT('',(3.94159343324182,10.0617154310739,-4.));
#541=CARTESIAN_POINT('',(4.10472477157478,10.3650652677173,-4.));
#542=CARTESIAN_POINT('',(4.43231807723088,10.9710255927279,-4.));
#543=CARTESIAN_POINT('',(4.59677997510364,11.2736361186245,-4.));
#544=CARTESIAN_POINT('',(4.76174071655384,11.5759724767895,-4.));
#545=B_SPLINE_CURVE_WITH_KNOTS('',3,(#485,#486,#487,#488,#489,#490,#491,#492,#493,#494,#495,
#496,#497,#498,#499,#500,#501,#502,#503,#504,#505,#506,#507,#508,#509,#510,#511,#512,#513,#514,
#515,#516,#517,#518,#519,#520,#521,#522,#523,#524,#525,#526,#527,#528,#529,#530,#531,#532,#533,
#534,#535,#536,#537,#538,#539,#540,#541,#542,#543,#544),.UNSPECIFIED.,.F.,.F.,(4,2,2,2,2,2,2,2,
2,2,2,2,2,2,2,2,2,2,2,2,2,2,2,2,2,2,2,2,2,4),(0.,0.581704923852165,1.16350232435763,
1.74850946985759,2.33348864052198,2.93694794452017,3.54047524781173,4.14273896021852,
4.74481088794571,5.3435788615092,5.9422922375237,6.53323035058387,7.12418128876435,
7.54244285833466,7.96076253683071,8.79787772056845,9.22565783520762,9.65344071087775,
10.0810770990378,10.5087091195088,11.0712028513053,11.633726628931,12.1963530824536,
12.7589907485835,13.8852967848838,15.011642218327,16.0473185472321,17.0830279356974,
18.1163183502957,19.1495551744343),.UNSPECIFIED.);
#546=EDGE_CURVE('E366',#482,#60,#545,.T.);
#547=ORIENTED_EDGE('',*,*,#546,.T.);
#548=EDGE_CURVE('E367',#60,#431,#545,.T.);
#549=ORIENTED_EDGE('',*,*,#548,.T.);
#550=EDGE_LOOP('',(#474,#475,#476,#484,#547,#549));
#551=FACE_BOUND('',#550,.T.);
#552=ADVANCED_FACE('F159',(#551),#473,.T.);
#553=CARTESIAN_POINT('',(4.,-4.61880215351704,0.));
#554=DIRECTION('',(0.,0.866025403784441,0.499999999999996));
#555=DIRECTION('',(0.,-0.499999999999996,0.866025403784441));
#556=AXIS2_PLACEMENT_3D('',#553,#554,#555);
#557=PLANE('',#556);
#558=ORIENTED_EDGE('',*,*,#333,.F.);
#559=DIRECTION('',(-1.,0.,0.));
#560=VECTOR('',#559,1.);
#561=CARTESIAN_POINT('',(4.,-4.61880215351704,0.));
#562=LINE('',#561,#560);
#563=CARTESIAN_POINT('',(0.357265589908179,-4.61880215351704,0.));
#564=VERTEX_POINT('',#563);
#565=EDGE_CURVE('E337',#330,#564,#562,.T.);
#566=ORIENTED_EDGE('',*,*,#565,.T.);
#567=CARTESIAN_POINT('',(0.357332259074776,-2.30928560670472,-4.0002));
#568=CARTESIAN_POINT('',(0.298717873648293,-2.41077174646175,-3.82442084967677));
#569=CARTESIAN_POINT('',(0.245410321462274,-2.51313390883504,-3.64712438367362));
#570=CARTESIAN_POINT('',(0.152361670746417,-2.71963072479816,-3.28946140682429));
#571=CARTESIAN_POINT('',(0.112653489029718,-2.82376904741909,-3.10908854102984));
#572=CARTESIAN_POINT('',(0.050842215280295,-3.030755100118,-2.7505781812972));
#573=CARTESIAN_POINT('',(0.0283277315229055,-3.13357098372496,-2.57249584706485));
#574=CARTESIAN_POINT('',(0.00145062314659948,-3.33968651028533,-2.21549328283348));
#575=CARTESIAN_POINT('',(-0.00293425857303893,-3.44298540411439,-2.03657435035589));
#576=CARTESIAN_POINT('',(0.00619007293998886,-3.63600352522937,-1.70225715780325));
#577=CARTESIAN_POINT('',(0.0174589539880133,-3.72575165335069,-1.54680884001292));
#578=CARTESIAN_POINT('',(0.0531739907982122,-3.90466320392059,-1.23692494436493));
#579=CARTESIAN_POINT('',(0.0776323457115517,-3.99382600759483,-1.08249043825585));
#580=CARTESIAN_POINT('',(0.138776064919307,-4.17310641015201,-0.771967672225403));
#581=CARTESIAN_POINT('',(0.175720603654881,-4.26320131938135,-0.615918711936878));
#582=CARTESIAN_POINT('',(0.259570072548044,-4.44204742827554,-0.306148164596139));
#583=CARTESIAN_POINT('',(0.306455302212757,-4.5308009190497,-0.152422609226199));
#584=CARTESIAN_POINT('',(0.357332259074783,-4.61891762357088,0.000200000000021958));
#585=B_SPLINE_CURVE_WITH_KNOTS('',3,(#567,#568,#569,#570,#571,#572,#573,#574,#575,#576,#577,
#578,#579,#580,#581,#582,#583,#584),.UNSPECIFIED.,.F.,.F.,(4,2,2,2,2,2,2,2,4),(0.,
0.634047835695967,1.26961969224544,1.88946157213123,2.50854226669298,3.04757825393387,
3.58711366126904,4.13861653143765,4.68903648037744),.UNSPECIFIED.);
#586=EDGE_CURVE('E248',#64,#564,#585,.T.);
#587=ORIENTED_EDGE('',*,*,#586,.F.);
#588=EDGE_CURVE('E359',#482,#64,#585,.T.);
#589=ORIENTED_EDGE('',*,*,#588,.F.);
#590=ORIENTED_EDGE('',*,*,#483,.F.);
#591=ORIENTED_EDGE('',*,*,#302,.F.);
#592=EDGE_LOOP('',(#558,#566,#587,#589,#590,#591));
#593=FACE_BOUND('',#592,.T.);
#594=ADVANCED_FACE('F236',(#593),#557,.F.);
#595=CARTESIAN_POINT('',(4.,-2.30940107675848,4.));
#596=DIRECTION('',(0.,0.866025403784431,-0.500000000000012));
#597=DIRECTION('',(0.,0.500000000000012,0.866025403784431));
#598=AXIS2_PLACEMENT_3D('',#595,#596,#597);
#599=PLANE('',#598);
#600=ORIENTED_EDGE('',*,*,#404,.F.);
#601=DIRECTION('',(-1.,0.,0.));
#602=VECTOR('',#601,1.);
#603=CARTESIAN_POINT('',(4.,-2.30940107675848,4.));
#604=LINE('',#603,#602);
#605=CARTESIAN_POINT('',(0.357265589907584,-2.30940107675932,4.));
#606=VERTEX_POINT('',#605);
#607=EDGE_CURVE('E339',#401,#606,#604,.T.);
#608=ORIENTED_EDGE('',*,*,#607,.T.);
#609=CARTESIAN_POINT('',(0.357332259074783,-4.61891762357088,-0.000199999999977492));
#610=CARTESIAN_POINT('',(0.298717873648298,-4.51743148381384,0.17557915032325));
#611=CARTESIAN_POINT('',(0.245410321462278,-4.41506932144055,0.352875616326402));
#612=CARTESIAN_POINT('',(0.152361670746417,-4.20857250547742,0.710538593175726));
#613=CARTESIAN_POINT('',(0.112653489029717,-4.10443418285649,0.89091145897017));
#614=CARTESIAN_POINT('',(0.0508422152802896,-3.89744813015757,1.24942181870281));
#615=CARTESIAN_POINT('',(0.0283277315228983,-3.79463224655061,1.42750415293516));
#616=CARTESIAN_POINT('',(0.00145062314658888,-3.58851671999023,1.78450671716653));
#617=CARTESIAN_POINT('',(-0.0029342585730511,-3.48521782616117,1.96342564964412));
#618=CARTESIAN_POINT('',(0.0061900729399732,-3.29219970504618,2.29774284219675));
#619=CARTESIAN_POINT('',(0.0174589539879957,-3.20245157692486,2.45319115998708));
#620=CARTESIAN_POINT('',(0.053173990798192,-3.02354002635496,2.76307505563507));
#621=CARTESIAN_POINT('',(0.0776323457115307,-2.93437722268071,2.91750956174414));
#622=CARTESIAN_POINT('',(0.138776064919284,-2.75509682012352,3.22803232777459));
#623=CARTESIAN_POINT('',(0.175720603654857,-2.66500191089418,3.38408128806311));
#624=CARTESIAN_POINT('',(0.259570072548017,-2.48615580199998,3.69385183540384));
#625=CARTESIAN_POINT('',(0.306455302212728,-2.39740231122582,3.84757739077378));
#626=CARTESIAN_POINT('',(0.357332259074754,-2.30928560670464,4.0002));
#627=B_SPLINE_CURVE_WITH_KNOTS('',3,(#609,#610,#611,#612,#613,#614,#615,#616,#617,#618,#619,
#620,#621,#622,#623,#624,#625,#626),.UNSPECIFIED.,.F.,.F.,(4,2,2,2,2,2,2,2,4),(0.,
0.634047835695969,1.26961969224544,1.88946157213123,2.50854226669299,3.04757825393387,
3.58711366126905,4.13861653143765,4.68903648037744),.UNSPECIFIED.);
#628=EDGE_CURVE('E249',#41,#606,#627,.T.);
#629=ORIENTED_EDGE('',*,*,#628,.F.);
#630=EDGE_CURVE('E242',#564,#41,#627,.T.);
#631=ORIENTED_EDGE('',*,*,#630,.F.);
#632=ORIENTED_EDGE('',*,*,#565,.F.);
#633=ORIENTED_EDGE('',*,*,#331,.F.);
#634=EDGE_LOOP('',(#600,#608,#629,#631,#632,#633));
#635=FACE_BOUND('',#634,.T.);
#636=ADVANCED_FACE('F232',(#635),#599,.F.);
#637=CARTESIAN_POINT('',(4.,2.30940107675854,4.));
#638=DIRECTION('',(0.,0.,-1.));
#639=DIRECTION('',(-1.,0.,0.));
#640=AXIS2_PLACEMENT_3D('',#637,#638,#639);
#641=PLANE('',#640);
#642=ORIENTED_EDGE('',*,*,#414,.F.);
#643=DIRECTION('',(-1.,0.,0.));
#644=VECTOR('',#643,1.);
#645=CARTESIAN_POINT('',(4.,2.30940107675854,4.));
#646=LINE('',#645,#644);
#647=CARTESIAN_POINT('',(0.357265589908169,2.30940107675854,4.));
#648=VERTEX_POINT('',#647);
#649=EDGE_CURVE('E341',#411,#648,#646,.T.);
#650=ORIENTED_EDGE('',*,*,#649,.T.);
#651=CARTESIAN_POINT('',(1.94002519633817,-6.17841977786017,4.));
#652=CARTESIAN_POINT('',(1.85547938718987,-6.00392359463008,4.));
#653=CARTESIAN_POINT('',(1.77175147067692,-5.8290241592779,4.));
#654=CARTESIAN_POINT('',(1.60639192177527,-5.47820424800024,4.));
#655=CARTESIAN_POINT('',(1.52476062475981,-5.30228361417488,4.));
#656=CARTESIAN_POINT('',(1.3636387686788,-4.94828833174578,4.));
#657=CARTESIAN_POINT('',(1.28416250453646,-4.77020715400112,4.));
#658=CARTESIAN_POINT('',(1.12849580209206,-4.4126196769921,4.));
#659=CARTESIAN_POINT('',(1.05230520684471,-4.23311344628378,4.));
#660=CARTESIAN_POINT('',(0.901734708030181,-3.86668749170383,4.));
#661=CARTESIAN_POINT('',(0.827488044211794,-3.67971271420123,4.));
#662=CARTESIAN_POINT('',(0.684674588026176,-3.30356643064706,4.));
#663=CARTESIAN_POINT('',(0.616108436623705,-3.11439467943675,4.));
#664=CARTESIAN_POINT('',(0.486474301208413,-2.73391578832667,4.));
#665=CARTESIAN_POINT('',(0.425390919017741,-2.54261394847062,4.));
#666=CARTESIAN_POINT('',(0.31269889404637,-2.15726633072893,4.));
#667=CARTESIAN_POINT('',(0.261087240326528,-1.96322144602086,4.));
#668=CARTESIAN_POINT('',(0.170105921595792,-1.57335309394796,4.));
#669=CARTESIAN_POINT('',(0.130670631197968,-1.37754523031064,4.));
#670=CARTESIAN_POINT('',(0.0662871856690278,-0.983520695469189,4.));
#671=CARTESIAN_POINT('',(0.0413377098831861,-0.785304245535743,4.));
#672=CARTESIAN_POINT('',(0.00824333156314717,-0.390030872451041,4.));
#673=CARTESIAN_POINT('',(-0.000115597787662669,-0.19299232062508,4.));
#674=CARTESIAN_POINT('',(0.000117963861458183,0.201089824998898,4.));
#675=CARTESIAN_POINT('',(0.00871082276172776,0.398133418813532,4.));
#676=CARTESIAN_POINT('',(0.0371495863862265,0.733403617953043,4.));
#677=CARTESIAN_POINT('',(0.0529733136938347,0.871991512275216,4.));
#678=CARTESIAN_POINT('',(0.0920077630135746,1.14813026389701,4.));
#679=CARTESIAN_POINT('',(0.115219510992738,1.28568097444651,4.));
#680=CARTESIAN_POINT('',(0.194714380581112,1.69660728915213,4.));
#681=CARTESIAN_POINT('',(0.260841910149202,1.96809847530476,4.));
#682=CARTESIAN_POINT('',(0.375218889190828,2.3740080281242,4.));
#683=CARTESIAN_POINT('',(0.416399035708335,2.51053794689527,4.));
#684=CARTESIAN_POINT('',(0.502964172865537,2.78227101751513,4.));
#685=CARTESIAN_POINT('',(0.548349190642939,2.91747416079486,4.));
#686=CARTESIAN_POINT('',(0.642601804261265,3.18659783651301,4.));
#687=CARTESIAN_POINT('',(0.691468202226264,3.32051879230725,4.));
#688=CARTESIAN_POINT('',(0.792115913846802,3.58725614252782,4.));
#689=CARTESIAN_POINT('',(0.843897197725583,3.72007254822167,4.));
#690=CARTESIAN_POINT('',(0.966605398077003,4.02646162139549,4.));
#691=CARTESIAN_POINT('',(1.03842021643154,4.1996779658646,4.));
#692=CARTESIAN_POINT('',(1.1853893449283,4.54469195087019,4.));
#693=CARTESIAN_POINT('',(1.26054383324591,4.7164895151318,4.));
#694=CARTESIAN_POINT('',(1.41354083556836,5.05891813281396,4.));
#695=CARTESIAN_POINT('',(1.49138383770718,5.2295489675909,4.));
#696=CARTESIAN_POINT('',(1.64923960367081,5.56980548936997,4.));
#697=CARTESIAN_POINT('',(1.72925241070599,5.7394311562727,4.));
#698=CARTESIAN_POINT('',(1.97207835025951,6.24735568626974,4.));
#699=CARTESIAN_POINT('',(2.13753726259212,6.5843890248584,4.));
#700=CARTESIAN_POINT('',(2.47327901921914,7.25604338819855,4.));
#701=CARTESIAN_POINT('',(2.64356203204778,7.59066432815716,4.));
#702=CARTESIAN_POINT('',(2.97373372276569,8.23125888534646,4.));
#703=CARTESIAN_POINT('',(3.13335569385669,8.53737022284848,4.));
#704=CARTESIAN_POINT('',(3.45480444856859,9.14844363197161,4.));
#705=CARTESIAN_POINT('',(3.61663130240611,9.45340566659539,4.));
#706=CARTESIAN_POINT('',(3.94159343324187,10.061715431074,4.));
#707=CARTESIAN_POINT('',(4.10472477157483,10.3650652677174,4.));
#708=CARTESIAN_POINT('',(4.43231807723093,10.971025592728,4.));
#709=CARTESIAN_POINT('',(4.59677997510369,11.2736361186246,4.));
#710=CARTESIAN_POINT('',(4.76174071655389,11.5759724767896,4.));
#711=B_SPLINE_CURVE_WITH_KNOTS('',3,(#651,#652,#653,#654,#655,#656,#657,#658,#659,#660,#661,
#662,#663,#664,#665,#666,#667,#668,#669,#670,#671,#672,#673,#674,#675,#676,#677,#678,#679,#680,
#681,#682,#683,#684,#685,#686,#687,#688,#689,#690,#691,#692,#693,#694,#695,#696,#697,#698,#699,
#700,#701,#702,#703,#704,#705,#706,#707,#708,#709,#710),.UNSPECIFIED.,.F.,.F.,(4,2,2,2,2,2,2,2,
2,2,2,2,2,2,2,2,2,2,2,2,2,2,2,2,2,2,2,2,2,4),(0.,0.581704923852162,1.16350232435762,
1.74850946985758,2.33348864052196,2.93694794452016,3.54047524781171,4.1427389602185,
4.74481088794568,5.34357886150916,5.94229223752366,6.53323035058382,7.1241812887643,
7.54244285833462,7.96076253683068,8.79787772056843,9.2256578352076,9.65344071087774,
10.0810770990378,10.5087091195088,11.0712028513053,11.6337266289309,12.1963530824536,
12.7589907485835,13.8852967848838,15.011642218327,16.0473185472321,17.0830279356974,
18.1163183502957,19.1495551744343),.UNSPECIFIED.);
#712=EDGE_CURVE('E247',#43,#648,#711,.T.);
#713=ORIENTED_EDGE('',*,*,#712,.F.);
#714=EDGE_CURVE('E258',#606,#43,#711,.T.);
#715=ORIENTED_EDGE('',*,*,#714,.F.);
#716=ORIENTED_EDGE('',*,*,#607,.F.);
#717=ORIENTED_EDGE('',*,*,#402,.F.);
#718=EDGE_LOOP('',(#642,#650,#713,#715,#716,#717));
#719=FACE_BOUND('',#718,.T.);
#720=ADVANCED_FACE('F235',(#719),#641,.F.);
#721=CARTESIAN_POINT('',(4.,4.61880215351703,0.));
#722=DIRECTION('',(0.,-0.866025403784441,-0.499999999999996));
#723=DIRECTION('',(0.,0.499999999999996,-0.866025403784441));
#724=AXIS2_PLACEMENT_3D('',#721,#722,#723);
#725=PLANE('',#724);
#726=ORIENTED_EDGE('',*,*,#183,.F.);
#727=ORIENTED_EDGE('',*,*,#463,.T.);
#728=CARTESIAN_POINT('',(0.357332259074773,2.30928560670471,4.0002));
#729=CARTESIAN_POINT('',(0.29871787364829,2.41077174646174,3.82442084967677));
#730=CARTESIAN_POINT('',(0.245410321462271,2.51313390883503,3.64712438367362));
#731=CARTESIAN_POINT('',(0.152361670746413,2.71963072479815,3.28946140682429));
#732=CARTESIAN_POINT('',(0.112653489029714,2.82376904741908,3.10908854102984));
#733=CARTESIAN_POINT('',(0.0508422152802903,3.03075510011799,2.7505781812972));
#734=CARTESIAN_POINT('',(0.0283277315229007,3.13357098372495,2.57249584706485));
#735=CARTESIAN_POINT('',(0.00145062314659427,3.33968651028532,2.21549328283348));
#736=CARTESIAN_POINT('',(-0.00293425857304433,3.44298540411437,2.03657435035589));
#737=CARTESIAN_POINT('',(0.00619007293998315,3.63600352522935,1.70225715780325));
#738=CARTESIAN_POINT('',(0.0174589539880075,3.72575165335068,1.54680884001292));
#739=CARTESIAN_POINT('',(0.0531739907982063,3.90466320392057,1.23692494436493));
#740=CARTESIAN_POINT('',(0.0776323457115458,3.99382600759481,1.08249043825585));
#741=CARTESIAN_POINT('',(0.138776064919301,4.173106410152,0.771967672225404));
#742=CARTESIAN_POINT('',(0.175720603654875,4.26320131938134,0.615918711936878));
#743=CARTESIAN_POINT('',(0.259570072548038,4.44204742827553,0.30614816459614));
#744=CARTESIAN_POINT('',(0.30645530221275,4.53080091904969,0.152422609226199));
#745=CARTESIAN_POINT('',(0.357332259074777,4.61891762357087,-0.000200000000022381));
#746=B_SPLINE_CURVE_WITH_KNOTS('',3,(#728,#729,#730,#731,#732,#733,#734,#735,#736,#737,#738,
#739,#740,#741,#742,#743,#744,#745),.UNSPECIFIED.,.F.,.F.,(4,2,2,2,2,2,2,2,4),(0.,
0.634047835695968,1.26961969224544,1.88946157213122,2.50854226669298,3.04757825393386,
3.58711366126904,4.13861653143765,4.68903648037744),.UNSPECIFIED.);
#747=EDGE_CURVE('E250',#52,#456,#746,.T.);
#748=ORIENTED_EDGE('',*,*,#747,.F.);
#749=EDGE_CURVE('E362',#648,#52,#746,.T.);
#750=ORIENTED_EDGE('',*,*,#749,.F.);
#751=ORIENTED_EDGE('',*,*,#649,.F.);
#752=ORIENTED_EDGE('',*,*,#412,.F.);
#753=EDGE_LOOP('',(#726,#727,#748,#750,#751,#752));
#754=FACE_BOUND('',#753,.T.);
#755=ADVANCED_FACE('F390',(#754),#725,.F.);
#756=CARTESIAN_POINT('',(0.,0.,0.));
#757=DIRECTION('',(1.,0.,0.));
#758=DIRECTION('',(0.,0.,-1.));
#759=AXIS2_PLACEMENT_3D('',#756,#757,#758);
#760=CONICAL_SURFACE('',#759,4.,1.0471975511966);
#761=ORIENTED_EDGE('',*,*,#628,.T.);
#762=ORIENTED_EDGE('',*,*,#714,.T.);
#763=ORIENTED_EDGE('',*,*,#44,.F.);
#764=EDGE_LOOP('',(#761,#762,#763));
#765=FACE_BOUND('',#764,.T.);
#766=ADVANCED_FACE('F396',(#765),#760,.T.);
#767=ORIENTED_EDGE('',*,*,#630,.T.);
#768=ORIENTED_EDGE('',*,*,#67,.F.);
#769=ORIENTED_EDGE('',*,*,#586,.T.);
#770=EDGE_LOOP('',(#767,#768,#769));
#771=FACE_BOUND('',#770,.T.);
#772=ADVANCED_FACE('F402',(#771),#760,.T.);
#773=ORIENTED_EDGE('',*,*,#588,.T.);
#774=ORIENTED_EDGE('',*,*,#65,.F.);
#775=ORIENTED_EDGE('',*,*,#546,.F.);
#776=EDGE_LOOP('',(#773,#774,#775));
#777=FACE_BOUND('',#776,.T.);
#778=ADVANCED_FACE('F409',(#777),#760,.T.);
#779=ORIENTED_EDGE('',*,*,#61,.F.);
#780=ORIENTED_EDGE('',*,*,#453,.T.);
#781=ORIENTED_EDGE('',*,*,#548,.F.);
#782=EDGE_LOOP('',(#779,#780,#781));
#783=FACE_BOUND('',#782,.T.);
#784=ADVANCED_FACE('F194',(#783),#760,.T.);
#785=ORIENTED_EDGE('',*,*,#747,.T.);
#786=ORIENTED_EDGE('',*,*,#457,.T.);
#787=ORIENTED_EDGE('',*,*,#57,.F.);
#788=EDGE_LOOP('',(#785,#786,#787));
#789=FACE_BOUND('',#788,.T.);
#790=ADVANCED_FACE('F410',(#789),#760,.T.);
#791=ORIENTED_EDGE('',*,*,#712,.T.);
#792=ORIENTED_EDGE('',*,*,#749,.T.);
#793=ORIENTED_EDGE('',*,*,#53,.F.);
#794=EDGE_LOOP('',(#791,#792,#793));
#795=FACE_BOUND('',#794,.T.);
#796=ADVANCED_FACE('F403',(#795),#760,.T.);
#797=CARTESIAN_POINT('',(0.,0.,0.));
#798=DIRECTION('',(1.,0.,0.));
#799=DIRECTION('',(0.,0.,-1.));
#800=AXIS2_PLACEMENT_3D('',#797,#798,#799);
#801=CYLINDRICAL_SURFACE('',#800,2.5);
#802=ORIENTED_EDGE('',*,*,#31,.T.);
#803=EDGE_LOOP('',(#802));
#804=FACE_BOUND('',#803,.T.);
#805=CARTESIAN_POINT('',(0.0253999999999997,0.,0.));
#806=DIRECTION('',(1.,0.,0.));
#807=DIRECTION('',(0.,0.,-1.));
#808=AXIS2_PLACEMENT_3D('',#805,#806,#807);
#809=CIRCLE('',#808,2.5);
#810=CARTESIAN_POINT('',(0.0253999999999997,0.,-2.5));
#811=VERTEX_POINT('',#810);
#812=EDGE_CURVE('E302',#811,#811,#809,.T.);
#813=ORIENTED_EDGE('',*,*,#812,.T.);
#814=EDGE_LOOP('',(#813));
#815=FACE_BOUND('',#814,.T.);
#816=ADVANCED_FACE('F136',(#804,#815),#801,.F.);
#817=CARTESIAN_POINT('',(0.333491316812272,0.,0.));
#818=DIRECTION('',(-1.,0.,0.));
#819=DIRECTION('',(0.,0.,1.));
#820=AXIS2_PLACEMENT_3D('',#817,#818,#819);
#821=CONICAL_SURFACE('',#820,2.06,0.959931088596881);
#822=CARTESIAN_POINT('',(0.305483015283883,0.,0.));
#823=DIRECTION('',(-1.,0.,0.));
#824=DIRECTION('',(0.,0.,1.));
#825=AXIS2_PLACEMENT_3D('',#822,#823,#824);
#826=CIRCLE('',#825,2.1);
#827=CARTESIAN_POINT('',(0.305483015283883,0.,2.1));
#828=VERTEX_POINT('',#827);
#829=EDGE_CURVE('E185',#828,#828,#826,.F.);
#830=ORIENTED_EDGE('',*,*,#829,.T.);
#831=EDGE_LOOP('',(#830));
#832=FACE_BOUND('',#831,.T.);
#833=ORIENTED_EDGE('',*,*,#812,.F.);
#834=EDGE_LOOP('',(#833));
#835=FACE_BOUND('',#834,.T.);
#836=ADVANCED_FACE('F127',(#832,#835),#821,.F.);
#837=CARTESIAN_POINT('',(7.76180729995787,0.,0.));
#838=DIRECTION('',(-1.,0.,0.));
#839=DIRECTION('',(0.,0.,1.));
#840=AXIS2_PLACEMENT_3D('',#837,#838,#839);
#841=CONICAL_SURFACE('',#840,0.,1.02974425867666);
#842=CARTESIAN_POINT('',(6.5,0.,0.));
#843=DIRECTION('',(-1.,0.,0.));
#844=DIRECTION('',(0.,0.,1.));
#845=AXIS2_PLACEMENT_3D('',#842,#843,#844);
#846=CIRCLE('',#845,2.1);
#847=CARTESIAN_POINT('',(6.5,0.,2.1));
#848=VERTEX_POINT('',#847);
#849=EDGE_CURVE('E299',#848,#848,#846,.T.);
#850=ORIENTED_EDGE('',*,*,#849,.T.);
#851=EDGE_LOOP('',(#850));
#852=FACE_BOUND('',#851,.T.);
#853=CARTESIAN_POINT('',(7.76180729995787,0.,0.));
#854=VERTEX_POINT('',#853);
#855=VERTEX_LOOP('',#854);
#856=FACE_BOUND('',#855,.T.);
#857=ADVANCED_FACE('F124',(#852,#856),#841,.F.);
#858=CARTESIAN_POINT('',(0.,0.,0.));
#859=DIRECTION('',(-1.,0.,0.));
#860=DIRECTION('',(0.,0.,1.));
#861=AXIS2_PLACEMENT_3D('',#858,#859,#860);
#862=CYLINDRICAL_SURFACE('',#861,2.1);
#863=ORIENTED_EDGE('',*,*,#829,.F.);
#864=EDGE_LOOP('',(#863));
#865=FACE_BOUND('',#864,.T.);
#866=ORIENTED_EDGE('',*,*,#849,.F.);
#867=EDGE_LOOP('',(#866));
#868=FACE_BOUND('',#867,.T.);
#869=ADVANCED_FACE('F126',(#865,#868),#862,.F.);
#870=CARTESIAN_POINT('',(4.12,0.,0.));
#871=DIRECTION('',(-1.,0.,0.));
#872=DIRECTION('',(0.,0.,1.));
#873=AXIS2_PLACEMENT_3D('',#870,#871,#872);
#874=TOROIDAL_SURFACE('',#873,3.87,0.12);
#875=ORIENTED_EDGE('',*,*,#84,.F.);
#876=EDGE_LOOP('',(#875));
#877=FACE_BOUND('',#876,.T.);
#878=ORIENTED_EDGE('',*,*,#132,.F.);
#879=EDGE_LOOP('',(#878));
#880=FACE_BOUND('',#879,.T.);
#881=ADVANCED_FACE('F34',(#877,#880),#874,.F.);
#882=CLOSED_SHELL('',(#71,#119,#147,#156,#209,#280,#309,#338,#409,#419,#468,#552,#594,#636,#720,
#755,#766,#772,#778,#784,#790,#796,#816,#836,#857,#869,#881));
#883=MANIFOLD_SOLID_BREP('B2',#882);
#884=ADVANCED_BREP_SHAPE_REPRESENTATION('',(#18,#883),#14);
#885=SHAPE_DEFINITION_REPRESENTATION(#9,#884);
ENDSEC;
END-ISO-10303-21;
